VERSION 5.7 ;
  NOWIREEXTENSIONATPIN ON ;
  DIVIDERCHAR "/" ;
  BUSBITCHARS "[]" ;
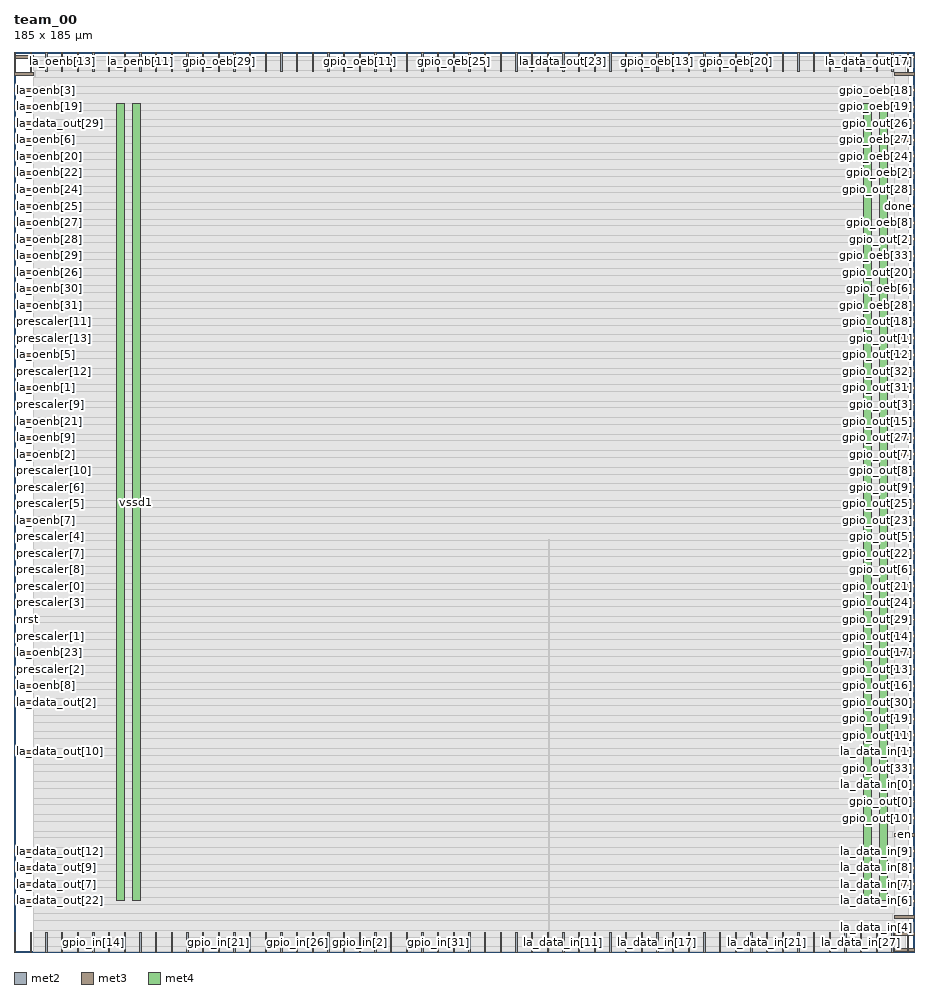
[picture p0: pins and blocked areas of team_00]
MACRO team_00
  CLASS BLOCK ;
  FOREIGN team_00 ;
  ORIGIN 0.000 0.000 ;
  SIZE 185.000 BY 185.000 ;
  PIN clk
    DIRECTION INPUT ;
    USE SIGNAL ;
    ANTENNAGATEAREA 1.286700 ;
    ANTENNADIFFAREA 0.434700 ;
    PORT
      LAYER met2 ;
        RECT 67.710 0.000 67.990 4.000 ;
    END
  END clk
  PIN done
    DIRECTION OUTPUT ;
    USE SIGNAL ;
    ANTENNADIFFAREA 0.445500 ;
    PORT
      LAYER met3 ;
        RECT 181.000 153.040 185.000 153.640 ;
    END
  END done
  PIN en
    DIRECTION INPUT ;
    USE SIGNAL ;
    ANTENNAGATEAREA 0.647700 ;
    ANTENNADIFFAREA 0.434700 ;
    PORT
      LAYER met3 ;
        RECT 181.000 23.840 185.000 24.440 ;
    END
  END en
  PIN gpio_in[0]
    DIRECTION INPUT ;
    USE SIGNAL ;
    PORT
      LAYER met2 ;
        RECT 0.090 0.000 0.370 4.000 ;
    END
  END gpio_in[0]
  PIN gpio_in[10]
    DIRECTION INPUT ;
    USE SIGNAL ;
    PORT
      LAYER met2 ;
        RECT 3.310 0.000 3.590 4.000 ;
    END
  END gpio_in[10]
  PIN gpio_in[11]
    DIRECTION INPUT ;
    USE SIGNAL ;
    PORT
      LAYER met2 ;
        RECT 6.530 0.000 6.810 4.000 ;
    END
  END gpio_in[11]
  PIN gpio_in[12]
    DIRECTION INPUT ;
    USE SIGNAL ;
    PORT
      LAYER met2 ;
        RECT 9.750 0.000 10.030 4.000 ;
    END
  END gpio_in[12]
  PIN gpio_in[13]
    DIRECTION INPUT ;
    USE SIGNAL ;
    PORT
      LAYER met2 ;
        RECT 12.970 0.000 13.250 4.000 ;
    END
  END gpio_in[13]
  PIN gpio_in[14]
    DIRECTION INPUT ;
    USE SIGNAL ;
    PORT
      LAYER met2 ;
        RECT 16.190 0.000 16.470 4.000 ;
    END
  END gpio_in[14]
  PIN gpio_in[15]
    DIRECTION INPUT ;
    USE SIGNAL ;
    PORT
      LAYER met2 ;
        RECT 19.410 0.000 19.690 4.000 ;
    END
  END gpio_in[15]
  PIN gpio_in[16]
    DIRECTION INPUT ;
    USE SIGNAL ;
    PORT
      LAYER met2 ;
        RECT 22.630 0.000 22.910 4.000 ;
    END
  END gpio_in[16]
  PIN gpio_in[17]
    DIRECTION INPUT ;
    USE SIGNAL ;
    PORT
      LAYER met2 ;
        RECT 25.850 0.000 26.130 4.000 ;
    END
  END gpio_in[17]
  PIN gpio_in[18]
    DIRECTION INPUT ;
    USE SIGNAL ;
    PORT
      LAYER met2 ;
        RECT 29.070 0.000 29.350 4.000 ;
    END
  END gpio_in[18]
  PIN gpio_in[19]
    DIRECTION INPUT ;
    USE SIGNAL ;
    PORT
      LAYER met2 ;
        RECT 32.290 0.000 32.570 4.000 ;
    END
  END gpio_in[19]
  PIN gpio_in[1]
    DIRECTION INPUT ;
    USE SIGNAL ;
    PORT
      LAYER met2 ;
        RECT 35.510 0.000 35.790 4.000 ;
    END
  END gpio_in[1]
  PIN gpio_in[20]
    DIRECTION INPUT ;
    USE SIGNAL ;
    PORT
      LAYER met2 ;
        RECT 38.730 0.000 39.010 4.000 ;
    END
  END gpio_in[20]
  PIN gpio_in[21]
    DIRECTION INPUT ;
    USE SIGNAL ;
    PORT
      LAYER met2 ;
        RECT 41.950 0.000 42.230 4.000 ;
    END
  END gpio_in[21]
  PIN gpio_in[22]
    DIRECTION INPUT ;
    USE SIGNAL ;
    PORT
      LAYER met2 ;
        RECT 45.170 0.000 45.450 4.000 ;
    END
  END gpio_in[22]
  PIN gpio_in[23]
    DIRECTION INPUT ;
    USE SIGNAL ;
    PORT
      LAYER met2 ;
        RECT 48.390 0.000 48.670 4.000 ;
    END
  END gpio_in[23]
  PIN gpio_in[24]
    DIRECTION INPUT ;
    USE SIGNAL ;
    PORT
      LAYER met2 ;
        RECT 51.610 0.000 51.890 4.000 ;
    END
  END gpio_in[24]
  PIN gpio_in[25]
    DIRECTION INPUT ;
    USE SIGNAL ;
    PORT
      LAYER met2 ;
        RECT 54.830 0.000 55.110 4.000 ;
    END
  END gpio_in[25]
  PIN gpio_in[26]
    DIRECTION INPUT ;
    USE SIGNAL ;
    PORT
      LAYER met2 ;
        RECT 58.050 0.000 58.330 4.000 ;
    END
  END gpio_in[26]
  PIN gpio_in[27]
    DIRECTION INPUT ;
    USE SIGNAL ;
    PORT
      LAYER met2 ;
        RECT 61.270 0.000 61.550 4.000 ;
    END
  END gpio_in[27]
  PIN gpio_in[28]
    DIRECTION INPUT ;
    USE SIGNAL ;
    PORT
      LAYER met2 ;
        RECT 64.490 0.000 64.770 4.000 ;
    END
  END gpio_in[28]
  PIN gpio_in[29]
    DIRECTION INPUT ;
    USE SIGNAL ;
    PORT
      LAYER met2 ;
        RECT 77.370 0.000 77.650 4.000 ;
    END
  END gpio_in[29]
  PIN gpio_in[2]
    DIRECTION INPUT ;
    USE SIGNAL ;
    PORT
      LAYER met2 ;
        RECT 70.930 0.000 71.210 4.000 ;
    END
  END gpio_in[2]
  PIN gpio_in[30]
    DIRECTION INPUT ;
    USE SIGNAL ;
    PORT
      LAYER met2 ;
        RECT 74.150 0.000 74.430 4.000 ;
    END
  END gpio_in[30]
  PIN gpio_in[31]
    DIRECTION INPUT ;
    USE SIGNAL ;
    PORT
      LAYER met2 ;
        RECT 87.030 0.000 87.310 4.000 ;
    END
  END gpio_in[31]
  PIN gpio_in[32]
    DIRECTION INPUT ;
    USE SIGNAL ;
    PORT
      LAYER met2 ;
        RECT 80.590 0.000 80.870 4.000 ;
    END
  END gpio_in[32]
  PIN gpio_in[33]
    DIRECTION INPUT ;
    USE SIGNAL ;
    PORT
      LAYER met2 ;
        RECT 83.810 0.000 84.090 4.000 ;
    END
  END gpio_in[33]
  PIN gpio_in[3]
    DIRECTION INPUT ;
    USE SIGNAL ;
    PORT
      LAYER met2 ;
        RECT 96.690 0.000 96.970 4.000 ;
    END
  END gpio_in[3]
  PIN gpio_in[4]
    DIRECTION INPUT ;
    USE SIGNAL ;
    PORT
      LAYER met2 ;
        RECT 90.250 0.000 90.530 4.000 ;
    END
  END gpio_in[4]
  PIN gpio_in[5]
    DIRECTION INPUT ;
    USE SIGNAL ;
    PORT
      LAYER met2 ;
        RECT 93.470 0.000 93.750 4.000 ;
    END
  END gpio_in[5]
  PIN gpio_in[6]
    DIRECTION INPUT ;
    USE SIGNAL ;
    PORT
      LAYER met2 ;
        RECT 106.350 0.000 106.630 4.000 ;
    END
  END gpio_in[6]
  PIN gpio_in[7]
    DIRECTION INPUT ;
    USE SIGNAL ;
    PORT
      LAYER met2 ;
        RECT 99.910 0.000 100.190 4.000 ;
    END
  END gpio_in[7]
  PIN gpio_in[8]
    DIRECTION INPUT ;
    USE SIGNAL ;
    PORT
      LAYER met2 ;
        RECT 103.130 0.000 103.410 4.000 ;
    END
  END gpio_in[8]
  PIN gpio_in[9]
    DIRECTION INPUT ;
    USE SIGNAL ;
    PORT
      LAYER met2 ;
        RECT 116.010 0.000 116.290 4.000 ;
    END
  END gpio_in[9]
  PIN gpio_oeb[0]
    DIRECTION OUTPUT ;
    USE SIGNAL ;
    ANTENNADIFFAREA 0.445500 ;
    PORT
      LAYER met2 ;
        RECT 29.070 181.000 29.350 185.000 ;
    END
  END gpio_oeb[0]
  PIN gpio_oeb[10]
    DIRECTION OUTPUT ;
    USE SIGNAL ;
    ANTENNADIFFAREA 0.445500 ;
    PORT
      LAYER met2 ;
        RECT 61.270 181.000 61.550 185.000 ;
    END
  END gpio_oeb[10]
  PIN gpio_oeb[11]
    DIRECTION OUTPUT ;
    USE SIGNAL ;
    ANTENNADIFFAREA 0.445500 ;
    PORT
      LAYER met2 ;
        RECT 70.930 181.000 71.210 185.000 ;
    END
  END gpio_oeb[11]
  PIN gpio_oeb[12]
    DIRECTION OUTPUT ;
    USE SIGNAL ;
    ANTENNADIFFAREA 0.445500 ;
    PORT
      LAYER met3 ;
        RECT 181.000 183.640 185.000 184.240 ;
    END
  END gpio_oeb[12]
  PIN gpio_oeb[13]
    DIRECTION OUTPUT ;
    USE SIGNAL ;
    ANTENNADIFFAREA 0.445500 ;
    PORT
      LAYER met2 ;
        RECT 132.110 181.000 132.390 185.000 ;
    END
  END gpio_oeb[13]
  PIN gpio_oeb[14]
    DIRECTION OUTPUT ;
    USE SIGNAL ;
    ANTENNADIFFAREA 0.445500 ;
    PORT
      LAYER met2 ;
        RECT 135.330 181.000 135.610 185.000 ;
    END
  END gpio_oeb[14]
  PIN gpio_oeb[15]
    DIRECTION OUTPUT ;
    USE SIGNAL ;
    ANTENNADIFFAREA 0.445500 ;
    PORT
      LAYER met2 ;
        RECT 51.610 181.000 51.890 185.000 ;
    END
  END gpio_oeb[15]
  PIN gpio_oeb[16]
    DIRECTION OUTPUT ;
    USE SIGNAL ;
    ANTENNADIFFAREA 0.445500 ;
    PORT
      LAYER met2 ;
        RECT 58.050 181.000 58.330 185.000 ;
    END
  END gpio_oeb[16]
  PIN gpio_oeb[17]
    DIRECTION OUTPUT ;
    USE SIGNAL ;
    ANTENNADIFFAREA 0.445500 ;
    PORT
      LAYER met2 ;
        RECT 45.170 181.000 45.450 185.000 ;
    END
  END gpio_oeb[17]
  PIN gpio_oeb[18]
    DIRECTION OUTPUT ;
    USE SIGNAL ;
    ANTENNADIFFAREA 0.445500 ;
    PORT
      LAYER met3 ;
        RECT 181.000 176.840 185.000 177.440 ;
    END
  END gpio_oeb[18]
  PIN gpio_oeb[19]
    DIRECTION OUTPUT ;
    USE SIGNAL ;
    ANTENNADIFFAREA 0.445500 ;
    PORT
      LAYER met3 ;
        RECT 181.000 173.440 185.000 174.040 ;
    END
  END gpio_oeb[19]
  PIN gpio_oeb[1]
    DIRECTION OUTPUT ;
    USE SIGNAL ;
    ANTENNADIFFAREA 0.445500 ;
    PORT
      LAYER met2 ;
        RECT 67.710 181.000 67.990 185.000 ;
    END
  END gpio_oeb[1]
  PIN gpio_oeb[20]
    DIRECTION OUTPUT ;
    USE SIGNAL ;
    ANTENNADIFFAREA 0.445500 ;
    PORT
      LAYER met2 ;
        RECT 148.210 181.000 148.490 185.000 ;
    END
  END gpio_oeb[20]
  PIN gpio_oeb[21]
    DIRECTION OUTPUT ;
    USE SIGNAL ;
    ANTENNADIFFAREA 0.445500 ;
    PORT
      LAYER met2 ;
        RECT 138.550 181.000 138.830 185.000 ;
    END
  END gpio_oeb[21]
  PIN gpio_oeb[22]
    DIRECTION OUTPUT ;
    USE SIGNAL ;
    ANTENNADIFFAREA 0.445500 ;
    PORT
      LAYER met2 ;
        RECT 74.150 181.000 74.430 185.000 ;
    END
  END gpio_oeb[22]
  PIN gpio_oeb[23]
    DIRECTION OUTPUT ;
    USE SIGNAL ;
    ANTENNADIFFAREA 0.445500 ;
    PORT
      LAYER met2 ;
        RECT 106.350 181.000 106.630 185.000 ;
    END
  END gpio_oeb[23]
  PIN gpio_oeb[24]
    DIRECTION OUTPUT ;
    USE SIGNAL ;
    ANTENNADIFFAREA 0.445500 ;
    PORT
      LAYER met3 ;
        RECT 181.000 163.240 185.000 163.840 ;
    END
  END gpio_oeb[24]
  PIN gpio_oeb[25]
    DIRECTION OUTPUT ;
    USE SIGNAL ;
    ANTENNADIFFAREA 0.445500 ;
    PORT
      LAYER met2 ;
        RECT 90.250 181.000 90.530 185.000 ;
    END
  END gpio_oeb[25]
  PIN gpio_oeb[26]
    DIRECTION OUTPUT ;
    USE SIGNAL ;
    ANTENNADIFFAREA 0.445500 ;
    PORT
      LAYER met2 ;
        RECT 80.590 181.000 80.870 185.000 ;
    END
  END gpio_oeb[26]
  PIN gpio_oeb[27]
    DIRECTION OUTPUT ;
    USE SIGNAL ;
    ANTENNADIFFAREA 0.445500 ;
    PORT
      LAYER met3 ;
        RECT 181.000 166.640 185.000 167.240 ;
    END
  END gpio_oeb[27]
  PIN gpio_oeb[28]
    DIRECTION OUTPUT ;
    USE SIGNAL ;
    ANTENNADIFFAREA 0.445500 ;
    PORT
      LAYER met3 ;
        RECT 181.000 132.640 185.000 133.240 ;
    END
  END gpio_oeb[28]
  PIN gpio_oeb[29]
    DIRECTION OUTPUT ;
    USE SIGNAL ;
    ANTENNADIFFAREA 0.445500 ;
    PORT
      LAYER met2 ;
        RECT 41.950 181.000 42.230 185.000 ;
    END
  END gpio_oeb[29]
  PIN gpio_oeb[2]
    DIRECTION OUTPUT ;
    USE SIGNAL ;
    ANTENNADIFFAREA 0.445500 ;
    PORT
      LAYER met3 ;
        RECT 181.000 159.840 185.000 160.440 ;
    END
  END gpio_oeb[2]
  PIN gpio_oeb[30]
    DIRECTION OUTPUT ;
    USE SIGNAL ;
    ANTENNADIFFAREA 0.445500 ;
    PORT
      LAYER met2 ;
        RECT 83.810 181.000 84.090 185.000 ;
    END
  END gpio_oeb[30]
  PIN gpio_oeb[31]
    DIRECTION OUTPUT ;
    USE SIGNAL ;
    ANTENNADIFFAREA 0.445500 ;
    PORT
      LAYER met2 ;
        RECT 32.290 181.000 32.570 185.000 ;
    END
  END gpio_oeb[31]
  PIN gpio_oeb[32]
    DIRECTION OUTPUT ;
    USE SIGNAL ;
    ANTENNADIFFAREA 0.445500 ;
    PORT
      LAYER met2 ;
        RECT 77.370 181.000 77.650 185.000 ;
    END
  END gpio_oeb[32]
  PIN gpio_oeb[33]
    DIRECTION OUTPUT ;
    USE SIGNAL ;
    ANTENNADIFFAREA 0.445500 ;
    PORT
      LAYER met3 ;
        RECT 181.000 142.840 185.000 143.440 ;
    END
  END gpio_oeb[33]
  PIN gpio_oeb[3]
    DIRECTION OUTPUT ;
    USE SIGNAL ;
    ANTENNADIFFAREA 0.445500 ;
    PORT
      LAYER met2 ;
        RECT 122.450 181.000 122.730 185.000 ;
    END
  END gpio_oeb[3]
  PIN gpio_oeb[4]
    DIRECTION OUTPUT ;
    USE SIGNAL ;
    ANTENNADIFFAREA 0.445500 ;
    PORT
      LAYER met2 ;
        RECT 99.910 181.000 100.190 185.000 ;
    END
  END gpio_oeb[4]
  PIN gpio_oeb[5]
    DIRECTION OUTPUT ;
    USE SIGNAL ;
    ANTENNADIFFAREA 0.445500 ;
    PORT
      LAYER met2 ;
        RECT 48.390 181.000 48.670 185.000 ;
    END
  END gpio_oeb[5]
  PIN gpio_oeb[6]
    DIRECTION OUTPUT ;
    USE SIGNAL ;
    ANTENNADIFFAREA 0.445500 ;
    PORT
      LAYER met3 ;
        RECT 181.000 136.040 185.000 136.640 ;
    END
  END gpio_oeb[6]
  PIN gpio_oeb[7]
    DIRECTION OUTPUT ;
    USE SIGNAL ;
    ANTENNADIFFAREA 0.445500 ;
    PORT
      LAYER met2 ;
        RECT 38.730 181.000 39.010 185.000 ;
    END
  END gpio_oeb[7]
  PIN gpio_oeb[8]
    DIRECTION OUTPUT ;
    USE SIGNAL ;
    ANTENNADIFFAREA 0.445500 ;
    PORT
      LAYER met3 ;
        RECT 181.000 149.640 185.000 150.240 ;
    END
  END gpio_oeb[8]
  PIN gpio_oeb[9]
    DIRECTION OUTPUT ;
    USE SIGNAL ;
    ANTENNADIFFAREA 0.445500 ;
    PORT
      LAYER met2 ;
        RECT 87.030 181.000 87.310 185.000 ;
    END
  END gpio_oeb[9]
  PIN gpio_out[0]
    DIRECTION OUTPUT ;
    USE SIGNAL ;
    ANTENNADIFFAREA 0.445500 ;
    PORT
      LAYER met3 ;
        RECT 181.000 30.640 185.000 31.240 ;
    END
  END gpio_out[0]
  PIN gpio_out[10]
    DIRECTION OUTPUT ;
    USE SIGNAL ;
    ANTENNADIFFAREA 0.445500 ;
    PORT
      LAYER met3 ;
        RECT 181.000 27.240 185.000 27.840 ;
    END
  END gpio_out[10]
  PIN gpio_out[11]
    DIRECTION OUTPUT ;
    USE SIGNAL ;
    ANTENNADIFFAREA 0.445500 ;
    PORT
      LAYER met3 ;
        RECT 181.000 44.240 185.000 44.840 ;
    END
  END gpio_out[11]
  PIN gpio_out[12]
    DIRECTION OUTPUT ;
    USE SIGNAL ;
    ANTENNADIFFAREA 0.445500 ;
    PORT
      LAYER met3 ;
        RECT 181.000 122.440 185.000 123.040 ;
    END
  END gpio_out[12]
  PIN gpio_out[13]
    DIRECTION OUTPUT ;
    USE SIGNAL ;
    ANTENNADIFFAREA 0.445500 ;
    PORT
      LAYER met3 ;
        RECT 181.000 57.840 185.000 58.440 ;
    END
  END gpio_out[13]
  PIN gpio_out[14]
    DIRECTION OUTPUT ;
    USE SIGNAL ;
    ANTENNADIFFAREA 0.445500 ;
    PORT
      LAYER met3 ;
        RECT 181.000 64.640 185.000 65.240 ;
    END
  END gpio_out[14]
  PIN gpio_out[15]
    DIRECTION OUTPUT ;
    USE SIGNAL ;
    ANTENNADIFFAREA 0.445500 ;
    PORT
      LAYER met3 ;
        RECT 181.000 108.840 185.000 109.440 ;
    END
  END gpio_out[15]
  PIN gpio_out[16]
    DIRECTION OUTPUT ;
    USE SIGNAL ;
    ANTENNADIFFAREA 0.445500 ;
    PORT
      LAYER met3 ;
        RECT 181.000 54.440 185.000 55.040 ;
    END
  END gpio_out[16]
  PIN gpio_out[17]
    DIRECTION OUTPUT ;
    USE SIGNAL ;
    ANTENNADIFFAREA 0.445500 ;
    PORT
      LAYER met3 ;
        RECT 181.000 61.240 185.000 61.840 ;
    END
  END gpio_out[17]
  PIN gpio_out[18]
    DIRECTION OUTPUT ;
    USE SIGNAL ;
    ANTENNADIFFAREA 0.445500 ;
    PORT
      LAYER met3 ;
        RECT 181.000 129.240 185.000 129.840 ;
    END
  END gpio_out[18]
  PIN gpio_out[19]
    DIRECTION OUTPUT ;
    USE SIGNAL ;
    ANTENNADIFFAREA 0.445500 ;
    PORT
      LAYER met3 ;
        RECT 181.000 47.640 185.000 48.240 ;
    END
  END gpio_out[19]
  PIN gpio_out[1]
    DIRECTION OUTPUT ;
    USE SIGNAL ;
    ANTENNADIFFAREA 0.445500 ;
    PORT
      LAYER met3 ;
        RECT 181.000 125.840 185.000 126.440 ;
    END
  END gpio_out[1]
  PIN gpio_out[20]
    DIRECTION OUTPUT ;
    USE SIGNAL ;
    ANTENNADIFFAREA 0.445500 ;
    PORT
      LAYER met3 ;
        RECT 181.000 139.440 185.000 140.040 ;
    END
  END gpio_out[20]
  PIN gpio_out[21]
    DIRECTION OUTPUT ;
    USE SIGNAL ;
    ANTENNADIFFAREA 0.445500 ;
    PORT
      LAYER met3 ;
        RECT 181.000 74.840 185.000 75.440 ;
    END
  END gpio_out[21]
  PIN gpio_out[22]
    DIRECTION OUTPUT ;
    USE SIGNAL ;
    ANTENNADIFFAREA 0.445500 ;
    PORT
      LAYER met3 ;
        RECT 181.000 81.640 185.000 82.240 ;
    END
  END gpio_out[22]
  PIN gpio_out[23]
    DIRECTION OUTPUT ;
    USE SIGNAL ;
    ANTENNADIFFAREA 0.445500 ;
    PORT
      LAYER met3 ;
        RECT 181.000 88.440 185.000 89.040 ;
    END
  END gpio_out[23]
  PIN gpio_out[24]
    DIRECTION OUTPUT ;
    USE SIGNAL ;
    ANTENNADIFFAREA 0.445500 ;
    PORT
      LAYER met3 ;
        RECT 181.000 71.440 185.000 72.040 ;
    END
  END gpio_out[24]
  PIN gpio_out[25]
    DIRECTION OUTPUT ;
    USE SIGNAL ;
    ANTENNADIFFAREA 0.445500 ;
    PORT
      LAYER met3 ;
        RECT 181.000 91.840 185.000 92.440 ;
    END
  END gpio_out[25]
  PIN gpio_out[26]
    DIRECTION OUTPUT ;
    USE SIGNAL ;
    ANTENNADIFFAREA 0.445500 ;
    PORT
      LAYER met3 ;
        RECT 181.000 170.040 185.000 170.640 ;
    END
  END gpio_out[26]
  PIN gpio_out[27]
    DIRECTION OUTPUT ;
    USE SIGNAL ;
    ANTENNADIFFAREA 0.445500 ;
    PORT
      LAYER met3 ;
        RECT 181.000 105.440 185.000 106.040 ;
    END
  END gpio_out[27]
  PIN gpio_out[28]
    DIRECTION OUTPUT ;
    USE SIGNAL ;
    ANTENNADIFFAREA 0.445500 ;
    PORT
      LAYER met3 ;
        RECT 181.000 156.440 185.000 157.040 ;
    END
  END gpio_out[28]
  PIN gpio_out[29]
    DIRECTION OUTPUT ;
    USE SIGNAL ;
    ANTENNADIFFAREA 0.445500 ;
    PORT
      LAYER met3 ;
        RECT 181.000 68.040 185.000 68.640 ;
    END
  END gpio_out[29]
  PIN gpio_out[2]
    DIRECTION OUTPUT ;
    USE SIGNAL ;
    ANTENNADIFFAREA 0.445500 ;
    PORT
      LAYER met3 ;
        RECT 181.000 146.240 185.000 146.840 ;
    END
  END gpio_out[2]
  PIN gpio_out[30]
    DIRECTION OUTPUT ;
    USE SIGNAL ;
    ANTENNADIFFAREA 0.445500 ;
    PORT
      LAYER met3 ;
        RECT 181.000 51.040 185.000 51.640 ;
    END
  END gpio_out[30]
  PIN gpio_out[31]
    DIRECTION OUTPUT ;
    USE SIGNAL ;
    ANTENNADIFFAREA 0.445500 ;
    PORT
      LAYER met3 ;
        RECT 181.000 115.640 185.000 116.240 ;
    END
  END gpio_out[31]
  PIN gpio_out[32]
    DIRECTION OUTPUT ;
    USE SIGNAL ;
    ANTENNADIFFAREA 0.445500 ;
    PORT
      LAYER met3 ;
        RECT 181.000 119.040 185.000 119.640 ;
    END
  END gpio_out[32]
  PIN gpio_out[33]
    DIRECTION OUTPUT ;
    USE SIGNAL ;
    ANTENNADIFFAREA 0.445500 ;
    PORT
      LAYER met3 ;
        RECT 181.000 37.440 185.000 38.040 ;
    END
  END gpio_out[33]
  PIN gpio_out[3]
    DIRECTION OUTPUT ;
    USE SIGNAL ;
    ANTENNADIFFAREA 0.445500 ;
    PORT
      LAYER met3 ;
        RECT 181.000 112.240 185.000 112.840 ;
    END
  END gpio_out[3]
  PIN gpio_out[4]
    DIRECTION OUTPUT ;
    USE SIGNAL ;
    ANTENNADIFFAREA 0.445500 ;
    PORT
      LAYER met3 ;
        RECT 181.000 180.240 185.000 180.840 ;
    END
  END gpio_out[4]
  PIN gpio_out[5]
    DIRECTION OUTPUT ;
    USE SIGNAL ;
    ANTENNADIFFAREA 0.445500 ;
    PORT
      LAYER met3 ;
        RECT 181.000 85.040 185.000 85.640 ;
    END
  END gpio_out[5]
  PIN gpio_out[6]
    DIRECTION OUTPUT ;
    USE SIGNAL ;
    ANTENNADIFFAREA 0.445500 ;
    PORT
      LAYER met3 ;
        RECT 181.000 78.240 185.000 78.840 ;
    END
  END gpio_out[6]
  PIN gpio_out[7]
    DIRECTION OUTPUT ;
    USE SIGNAL ;
    ANTENNADIFFAREA 0.445500 ;
    PORT
      LAYER met3 ;
        RECT 181.000 102.040 185.000 102.640 ;
    END
  END gpio_out[7]
  PIN gpio_out[8]
    DIRECTION OUTPUT ;
    USE SIGNAL ;
    ANTENNADIFFAREA 0.445500 ;
    PORT
      LAYER met3 ;
        RECT 181.000 98.640 185.000 99.240 ;
    END
  END gpio_out[8]
  PIN gpio_out[9]
    DIRECTION OUTPUT ;
    USE SIGNAL ;
    ANTENNADIFFAREA 0.445500 ;
    PORT
      LAYER met3 ;
        RECT 181.000 95.240 185.000 95.840 ;
    END
  END gpio_out[9]
  PIN la_data_in[0]
    DIRECTION INPUT ;
    USE SIGNAL ;
    ANTENNAGATEAREA 0.631200 ;
    ANTENNADIFFAREA 0.434700 ;
    PORT
      LAYER met3 ;
        RECT 181.000 34.040 185.000 34.640 ;
    END
  END la_data_in[0]
  PIN la_data_in[10]
    DIRECTION INPUT ;
    USE SIGNAL ;
    PORT
      LAYER met2 ;
        RECT 109.570 0.000 109.850 4.000 ;
    END
  END la_data_in[10]
  PIN la_data_in[11]
    DIRECTION INPUT ;
    USE SIGNAL ;
    PORT
      LAYER met2 ;
        RECT 112.790 0.000 113.070 4.000 ;
    END
  END la_data_in[11]
  PIN la_data_in[12]
    DIRECTION INPUT ;
    USE SIGNAL ;
    PORT
      LAYER met2 ;
        RECT 125.670 0.000 125.950 4.000 ;
    END
  END la_data_in[12]
  PIN la_data_in[13]
    DIRECTION INPUT ;
    USE SIGNAL ;
    PORT
      LAYER met2 ;
        RECT 119.230 0.000 119.510 4.000 ;
    END
  END la_data_in[13]
  PIN la_data_in[14]
    DIRECTION INPUT ;
    USE SIGNAL ;
    PORT
      LAYER met2 ;
        RECT 122.450 0.000 122.730 4.000 ;
    END
  END la_data_in[14]
  PIN la_data_in[15]
    DIRECTION INPUT ;
    USE SIGNAL ;
    PORT
      LAYER met2 ;
        RECT 135.330 0.000 135.610 4.000 ;
    END
  END la_data_in[15]
  PIN la_data_in[16]
    DIRECTION INPUT ;
    USE SIGNAL ;
    PORT
      LAYER met2 ;
        RECT 128.890 0.000 129.170 4.000 ;
    END
  END la_data_in[16]
  PIN la_data_in[17]
    DIRECTION INPUT ;
    USE SIGNAL ;
    PORT
      LAYER met2 ;
        RECT 132.110 0.000 132.390 4.000 ;
    END
  END la_data_in[17]
  PIN la_data_in[18]
    DIRECTION INPUT ;
    USE SIGNAL ;
    PORT
      LAYER met2 ;
        RECT 144.990 0.000 145.270 4.000 ;
    END
  END la_data_in[18]
  PIN la_data_in[19]
    DIRECTION INPUT ;
    USE SIGNAL ;
    PORT
      LAYER met2 ;
        RECT 138.550 0.000 138.830 4.000 ;
    END
  END la_data_in[19]
  PIN la_data_in[1]
    DIRECTION INPUT ;
    USE SIGNAL ;
    ANTENNAGATEAREA 0.631200 ;
    ANTENNADIFFAREA 0.434700 ;
    PORT
      LAYER met3 ;
        RECT 181.000 40.840 185.000 41.440 ;
    END
  END la_data_in[1]
  PIN la_data_in[20]
    DIRECTION INPUT ;
    USE SIGNAL ;
    PORT
      LAYER met2 ;
        RECT 141.770 0.000 142.050 4.000 ;
    END
  END la_data_in[20]
  PIN la_data_in[21]
    DIRECTION INPUT ;
    USE SIGNAL ;
    PORT
      LAYER met2 ;
        RECT 154.650 0.000 154.930 4.000 ;
    END
  END la_data_in[21]
  PIN la_data_in[22]
    DIRECTION INPUT ;
    USE SIGNAL ;
    PORT
      LAYER met2 ;
        RECT 148.210 0.000 148.490 4.000 ;
    END
  END la_data_in[22]
  PIN la_data_in[23]
    DIRECTION INPUT ;
    USE SIGNAL ;
    PORT
      LAYER met2 ;
        RECT 151.430 0.000 151.710 4.000 ;
    END
  END la_data_in[23]
  PIN la_data_in[24]
    DIRECTION INPUT ;
    USE SIGNAL ;
    PORT
      LAYER met2 ;
        RECT 164.310 0.000 164.590 4.000 ;
    END
  END la_data_in[24]
  PIN la_data_in[25]
    DIRECTION INPUT ;
    USE SIGNAL ;
    PORT
      LAYER met2 ;
        RECT 157.870 0.000 158.150 4.000 ;
    END
  END la_data_in[25]
  PIN la_data_in[26]
    DIRECTION INPUT ;
    USE SIGNAL ;
    PORT
      LAYER met2 ;
        RECT 161.090 0.000 161.370 4.000 ;
    END
  END la_data_in[26]
  PIN la_data_in[27]
    DIRECTION INPUT ;
    USE SIGNAL ;
    PORT
      LAYER met2 ;
        RECT 173.970 0.000 174.250 4.000 ;
    END
  END la_data_in[27]
  PIN la_data_in[28]
    DIRECTION INPUT ;
    USE SIGNAL ;
    PORT
      LAYER met2 ;
        RECT 167.530 0.000 167.810 4.000 ;
    END
  END la_data_in[28]
  PIN la_data_in[29]
    DIRECTION INPUT ;
    USE SIGNAL ;
    PORT
      LAYER met2 ;
        RECT 170.750 0.000 171.030 4.000 ;
    END
  END la_data_in[29]
  PIN la_data_in[2]
    DIRECTION INPUT ;
    USE SIGNAL ;
    PORT
      LAYER met2 ;
        RECT 183.630 0.000 183.910 4.000 ;
    END
  END la_data_in[2]
  PIN la_data_in[30]
    DIRECTION INPUT ;
    USE SIGNAL ;
    PORT
      LAYER met2 ;
        RECT 177.190 0.000 177.470 4.000 ;
    END
  END la_data_in[30]
  PIN la_data_in[31]
    DIRECTION INPUT ;
    USE SIGNAL ;
    PORT
      LAYER met2 ;
        RECT 180.410 0.000 180.690 4.000 ;
    END
  END la_data_in[31]
  PIN la_data_in[3]
    DIRECTION INPUT ;
    USE SIGNAL ;
    PORT
      LAYER met3 ;
        RECT 181.000 0.040 185.000 0.640 ;
    END
  END la_data_in[3]
  PIN la_data_in[4]
    DIRECTION INPUT ;
    USE SIGNAL ;
    PORT
      LAYER met3 ;
        RECT 181.000 3.440 185.000 4.040 ;
    END
  END la_data_in[4]
  PIN la_data_in[5]
    DIRECTION INPUT ;
    USE SIGNAL ;
    PORT
      LAYER met3 ;
        RECT 181.000 6.840 185.000 7.440 ;
    END
  END la_data_in[5]
  PIN la_data_in[6]
    DIRECTION INPUT ;
    USE SIGNAL ;
    PORT
      LAYER met3 ;
        RECT 181.000 10.240 185.000 10.840 ;
    END
  END la_data_in[6]
  PIN la_data_in[7]
    DIRECTION INPUT ;
    USE SIGNAL ;
    PORT
      LAYER met3 ;
        RECT 181.000 13.640 185.000 14.240 ;
    END
  END la_data_in[7]
  PIN la_data_in[8]
    DIRECTION INPUT ;
    USE SIGNAL ;
    PORT
      LAYER met3 ;
        RECT 181.000 17.040 185.000 17.640 ;
    END
  END la_data_in[8]
  PIN la_data_in[9]
    DIRECTION INPUT ;
    USE SIGNAL ;
    PORT
      LAYER met3 ;
        RECT 181.000 20.440 185.000 21.040 ;
    END
  END la_data_in[9]
  PIN la_data_out[0]
    DIRECTION OUTPUT ;
    USE SIGNAL ;
    PORT
      LAYER met2 ;
        RECT 22.630 181.000 22.910 185.000 ;
    END
  END la_data_out[0]
  PIN la_data_out[10]
    DIRECTION OUTPUT ;
    USE SIGNAL ;
    PORT
      LAYER met3 ;
        RECT 0.000 40.840 4.000 41.440 ;
    END
  END la_data_out[10]
  PIN la_data_out[11]
    DIRECTION OUTPUT ;
    USE SIGNAL ;
    PORT
      LAYER met2 ;
        RECT 64.490 181.000 64.770 185.000 ;
    END
  END la_data_out[11]
  PIN la_data_out[12]
    DIRECTION OUTPUT ;
    USE SIGNAL ;
    PORT
      LAYER met3 ;
        RECT 0.000 20.440 4.000 21.040 ;
    END
  END la_data_out[12]
  PIN la_data_out[13]
    DIRECTION OUTPUT ;
    USE SIGNAL ;
    PORT
      LAYER met2 ;
        RECT 128.890 181.000 129.170 185.000 ;
    END
  END la_data_out[13]
  PIN la_data_out[14]
    DIRECTION OUTPUT ;
    USE SIGNAL ;
    PORT
      LAYER met2 ;
        RECT 96.690 181.000 96.970 185.000 ;
    END
  END la_data_out[14]
  PIN la_data_out[15]
    DIRECTION OUTPUT ;
    USE SIGNAL ;
    PORT
      LAYER met2 ;
        RECT 154.650 181.000 154.930 185.000 ;
    END
  END la_data_out[15]
  PIN la_data_out[16]
    DIRECTION OUTPUT ;
    USE SIGNAL ;
    PORT
      LAYER met2 ;
        RECT 54.830 181.000 55.110 185.000 ;
    END
  END la_data_out[16]
  PIN la_data_out[17]
    DIRECTION OUTPUT ;
    USE SIGNAL ;
    PORT
      LAYER met2 ;
        RECT 180.410 181.000 180.690 185.000 ;
    END
  END la_data_out[17]
  PIN la_data_out[18]
    DIRECTION OUTPUT ;
    USE SIGNAL ;
    PORT
      LAYER met2 ;
        RECT 177.190 181.000 177.470 185.000 ;
    END
  END la_data_out[18]
  PIN la_data_out[19]
    DIRECTION OUTPUT ;
    USE SIGNAL ;
    PORT
      LAYER met2 ;
        RECT 144.990 181.000 145.270 185.000 ;
    END
  END la_data_out[19]
  PIN la_data_out[1]
    DIRECTION OUTPUT ;
    USE SIGNAL ;
    PORT
      LAYER met2 ;
        RECT 109.570 181.000 109.850 185.000 ;
    END
  END la_data_out[1]
  PIN la_data_out[20]
    DIRECTION OUTPUT ;
    USE SIGNAL ;
    PORT
      LAYER met2 ;
        RECT 170.750 181.000 171.030 185.000 ;
    END
  END la_data_out[20]
  PIN la_data_out[21]
    DIRECTION OUTPUT ;
    USE SIGNAL ;
    PORT
      LAYER met2 ;
        RECT 183.630 181.000 183.910 185.000 ;
    END
  END la_data_out[21]
  PIN la_data_out[22]
    DIRECTION OUTPUT ;
    USE SIGNAL ;
    PORT
      LAYER met3 ;
        RECT 0.000 10.240 4.000 10.840 ;
    END
  END la_data_out[22]
  PIN la_data_out[23]
    DIRECTION OUTPUT ;
    USE SIGNAL ;
    PORT
      LAYER met2 ;
        RECT 112.790 181.000 113.070 185.000 ;
    END
  END la_data_out[23]
  PIN la_data_out[24]
    DIRECTION OUTPUT ;
    USE SIGNAL ;
    PORT
      LAYER met2 ;
        RECT 119.230 181.000 119.510 185.000 ;
    END
  END la_data_out[24]
  PIN la_data_out[25]
    DIRECTION OUTPUT ;
    USE SIGNAL ;
    PORT
      LAYER met2 ;
        RECT 141.770 181.000 142.050 185.000 ;
    END
  END la_data_out[25]
  PIN la_data_out[26]
    DIRECTION OUTPUT ;
    USE SIGNAL ;
    PORT
      LAYER met2 ;
        RECT 157.870 181.000 158.150 185.000 ;
    END
  END la_data_out[26]
  PIN la_data_out[27]
    DIRECTION OUTPUT ;
    USE SIGNAL ;
    PORT
      LAYER met2 ;
        RECT 151.430 181.000 151.710 185.000 ;
    END
  END la_data_out[27]
  PIN la_data_out[28]
    DIRECTION OUTPUT ;
    USE SIGNAL ;
    PORT
      LAYER met2 ;
        RECT 167.530 181.000 167.810 185.000 ;
    END
  END la_data_out[28]
  PIN la_data_out[29]
    DIRECTION OUTPUT ;
    USE SIGNAL ;
    PORT
      LAYER met3 ;
        RECT 0.000 170.040 4.000 170.640 ;
    END
  END la_data_out[29]
  PIN la_data_out[2]
    DIRECTION OUTPUT ;
    USE SIGNAL ;
    PORT
      LAYER met3 ;
        RECT 0.000 51.040 4.000 51.640 ;
    END
  END la_data_out[2]
  PIN la_data_out[30]
    DIRECTION OUTPUT ;
    USE SIGNAL ;
    PORT
      LAYER met2 ;
        RECT 164.310 181.000 164.590 185.000 ;
    END
  END la_data_out[30]
  PIN la_data_out[31]
    DIRECTION OUTPUT ;
    USE SIGNAL ;
    PORT
      LAYER met2 ;
        RECT 116.010 181.000 116.290 185.000 ;
    END
  END la_data_out[31]
  PIN la_data_out[3]
    DIRECTION OUTPUT ;
    USE SIGNAL ;
    PORT
      LAYER met2 ;
        RECT 103.130 181.000 103.410 185.000 ;
    END
  END la_data_out[3]
  PIN la_data_out[4]
    DIRECTION OUTPUT ;
    USE SIGNAL ;
    PORT
      LAYER met2 ;
        RECT 161.090 181.000 161.370 185.000 ;
    END
  END la_data_out[4]
  PIN la_data_out[5]
    DIRECTION OUTPUT ;
    USE SIGNAL ;
    PORT
      LAYER met2 ;
        RECT 173.970 181.000 174.250 185.000 ;
    END
  END la_data_out[5]
  PIN la_data_out[6]
    DIRECTION OUTPUT ;
    USE SIGNAL ;
    PORT
      LAYER met2 ;
        RECT 35.510 181.000 35.790 185.000 ;
    END
  END la_data_out[6]
  PIN la_data_out[7]
    DIRECTION OUTPUT ;
    USE SIGNAL ;
    PORT
      LAYER met3 ;
        RECT 0.000 13.640 4.000 14.240 ;
    END
  END la_data_out[7]
  PIN la_data_out[8]
    DIRECTION OUTPUT ;
    USE SIGNAL ;
    PORT
      LAYER met2 ;
        RECT 125.670 181.000 125.950 185.000 ;
    END
  END la_data_out[8]
  PIN la_data_out[9]
    DIRECTION OUTPUT ;
    USE SIGNAL ;
    PORT
      LAYER met3 ;
        RECT 0.000 17.040 4.000 17.640 ;
    END
  END la_data_out[9]
  PIN la_oenb[0]
    DIRECTION INPUT ;
    USE SIGNAL ;
    ANTENNAGATEAREA 0.631200 ;
    ANTENNADIFFAREA 0.434700 ;
    PORT
      LAYER met2 ;
        RECT 93.470 181.000 93.750 185.000 ;
    END
  END la_oenb[0]
  PIN la_oenb[10]
    DIRECTION INPUT ;
    USE SIGNAL ;
    PORT
      LAYER met2 ;
        RECT 0.090 181.000 0.370 185.000 ;
    END
  END la_oenb[10]
  PIN la_oenb[11]
    DIRECTION INPUT ;
    USE SIGNAL ;
    PORT
      LAYER met2 ;
        RECT 25.850 181.000 26.130 185.000 ;
    END
  END la_oenb[11]
  PIN la_oenb[12]
    DIRECTION INPUT ;
    USE SIGNAL ;
    PORT
      LAYER met2 ;
        RECT 3.310 181.000 3.590 185.000 ;
    END
  END la_oenb[12]
  PIN la_oenb[13]
    DIRECTION INPUT ;
    USE SIGNAL ;
    PORT
      LAYER met2 ;
        RECT 9.750 181.000 10.030 185.000 ;
    END
  END la_oenb[13]
  PIN la_oenb[14]
    DIRECTION INPUT ;
    USE SIGNAL ;
    PORT
      LAYER met2 ;
        RECT 19.410 181.000 19.690 185.000 ;
    END
  END la_oenb[14]
  PIN la_oenb[15]
    DIRECTION INPUT ;
    USE SIGNAL ;
    PORT
      LAYER met2 ;
        RECT 6.530 181.000 6.810 185.000 ;
    END
  END la_oenb[15]
  PIN la_oenb[16]
    DIRECTION INPUT ;
    USE SIGNAL ;
    PORT
      LAYER met2 ;
        RECT 12.970 181.000 13.250 185.000 ;
    END
  END la_oenb[16]
  PIN la_oenb[17]
    DIRECTION INPUT ;
    USE SIGNAL ;
    PORT
      LAYER met2 ;
        RECT 16.190 181.000 16.470 185.000 ;
    END
  END la_oenb[17]
  PIN la_oenb[18]
    DIRECTION INPUT ;
    USE SIGNAL ;
    PORT
      LAYER met3 ;
        RECT 0.000 183.640 4.000 184.240 ;
    END
  END la_oenb[18]
  PIN la_oenb[19]
    DIRECTION INPUT ;
    USE SIGNAL ;
    PORT
      LAYER met3 ;
        RECT 0.000 173.440 4.000 174.040 ;
    END
  END la_oenb[19]
  PIN la_oenb[1]
    DIRECTION INPUT ;
    USE SIGNAL ;
    ANTENNAGATEAREA 0.631200 ;
    ANTENNADIFFAREA 0.434700 ;
    PORT
      LAYER met3 ;
        RECT 0.000 115.640 4.000 116.240 ;
    END
  END la_oenb[1]
  PIN la_oenb[20]
    DIRECTION INPUT ;
    USE SIGNAL ;
    PORT
      LAYER met3 ;
        RECT 0.000 163.240 4.000 163.840 ;
    END
  END la_oenb[20]
  PIN la_oenb[21]
    DIRECTION INPUT ;
    USE SIGNAL ;
    PORT
      LAYER met3 ;
        RECT 0.000 108.840 4.000 109.440 ;
    END
  END la_oenb[21]
  PIN la_oenb[22]
    DIRECTION INPUT ;
    USE SIGNAL ;
    PORT
      LAYER met3 ;
        RECT 0.000 159.840 4.000 160.440 ;
    END
  END la_oenb[22]
  PIN la_oenb[23]
    DIRECTION INPUT ;
    USE SIGNAL ;
    PORT
      LAYER met3 ;
        RECT 0.000 61.240 4.000 61.840 ;
    END
  END la_oenb[23]
  PIN la_oenb[24]
    DIRECTION INPUT ;
    USE SIGNAL ;
    PORT
      LAYER met3 ;
        RECT 0.000 156.440 4.000 157.040 ;
    END
  END la_oenb[24]
  PIN la_oenb[25]
    DIRECTION INPUT ;
    USE SIGNAL ;
    PORT
      LAYER met3 ;
        RECT 0.000 153.040 4.000 153.640 ;
    END
  END la_oenb[25]
  PIN la_oenb[26]
    DIRECTION INPUT ;
    USE SIGNAL ;
    PORT
      LAYER met3 ;
        RECT 0.000 139.440 4.000 140.040 ;
    END
  END la_oenb[26]
  PIN la_oenb[27]
    DIRECTION INPUT ;
    USE SIGNAL ;
    PORT
      LAYER met3 ;
        RECT 0.000 149.640 4.000 150.240 ;
    END
  END la_oenb[27]
  PIN la_oenb[28]
    DIRECTION INPUT ;
    USE SIGNAL ;
    PORT
      LAYER met3 ;
        RECT 0.000 146.240 4.000 146.840 ;
    END
  END la_oenb[28]
  PIN la_oenb[29]
    DIRECTION INPUT ;
    USE SIGNAL ;
    PORT
      LAYER met3 ;
        RECT 0.000 142.840 4.000 143.440 ;
    END
  END la_oenb[29]
  PIN la_oenb[2]
    DIRECTION INPUT ;
    USE SIGNAL ;
    PORT
      LAYER met3 ;
        RECT 0.000 102.040 4.000 102.640 ;
    END
  END la_oenb[2]
  PIN la_oenb[30]
    DIRECTION INPUT ;
    USE SIGNAL ;
    PORT
      LAYER met3 ;
        RECT 0.000 136.040 4.000 136.640 ;
    END
  END la_oenb[30]
  PIN la_oenb[31]
    DIRECTION INPUT ;
    USE SIGNAL ;
    PORT
      LAYER met3 ;
        RECT 0.000 132.640 4.000 133.240 ;
    END
  END la_oenb[31]
  PIN la_oenb[3]
    DIRECTION INPUT ;
    USE SIGNAL ;
    PORT
      LAYER met3 ;
        RECT 0.000 176.840 4.000 177.440 ;
    END
  END la_oenb[3]
  PIN la_oenb[4]
    DIRECTION INPUT ;
    USE SIGNAL ;
    PORT
      LAYER met3 ;
        RECT 0.000 180.240 4.000 180.840 ;
    END
  END la_oenb[4]
  PIN la_oenb[5]
    DIRECTION INPUT ;
    USE SIGNAL ;
    PORT
      LAYER met3 ;
        RECT 0.000 122.440 4.000 123.040 ;
    END
  END la_oenb[5]
  PIN la_oenb[6]
    DIRECTION INPUT ;
    USE SIGNAL ;
    PORT
      LAYER met3 ;
        RECT 0.000 166.640 4.000 167.240 ;
    END
  END la_oenb[6]
  PIN la_oenb[7]
    DIRECTION INPUT ;
    USE SIGNAL ;
    PORT
      LAYER met3 ;
        RECT 0.000 88.440 4.000 89.040 ;
    END
  END la_oenb[7]
  PIN la_oenb[8]
    DIRECTION INPUT ;
    USE SIGNAL ;
    PORT
      LAYER met3 ;
        RECT 0.000 54.440 4.000 55.040 ;
    END
  END la_oenb[8]
  PIN la_oenb[9]
    DIRECTION INPUT ;
    USE SIGNAL ;
    PORT
      LAYER met3 ;
        RECT 0.000 105.440 4.000 106.040 ;
    END
  END la_oenb[9]
  PIN nrst
    DIRECTION INPUT ;
    USE SIGNAL ;
    ANTENNAGATEAREA 0.647700 ;
    ANTENNADIFFAREA 0.434700 ;
    PORT
      LAYER met3 ;
        RECT 0.000 68.040 4.000 68.640 ;
    END
  END nrst
  PIN prescaler[0]
    DIRECTION INPUT ;
    USE SIGNAL ;
    ANTENNAGATEAREA 0.631200 ;
    ANTENNADIFFAREA 0.434700 ;
    PORT
      LAYER met3 ;
        RECT 0.000 74.840 4.000 75.440 ;
    END
  END prescaler[0]
  PIN prescaler[10]
    DIRECTION INPUT ;
    USE SIGNAL ;
    ANTENNAGATEAREA 0.647700 ;
    ANTENNADIFFAREA 0.434700 ;
    PORT
      LAYER met3 ;
        RECT 0.000 98.640 4.000 99.240 ;
    END
  END prescaler[10]
  PIN prescaler[11]
    DIRECTION INPUT ;
    USE SIGNAL ;
    ANTENNAGATEAREA 0.593700 ;
    ANTENNADIFFAREA 0.434700 ;
    PORT
      LAYER met3 ;
        RECT 0.000 129.240 4.000 129.840 ;
    END
  END prescaler[11]
  PIN prescaler[12]
    DIRECTION INPUT ;
    USE SIGNAL ;
    ANTENNAGATEAREA 0.647700 ;
    ANTENNADIFFAREA 0.434700 ;
    PORT
      LAYER met3 ;
        RECT 0.000 119.040 4.000 119.640 ;
    END
  END prescaler[12]
  PIN prescaler[13]
    DIRECTION INPUT ;
    USE SIGNAL ;
    ANTENNAGATEAREA 0.647700 ;
    ANTENNADIFFAREA 0.434700 ;
    PORT
      LAYER met3 ;
        RECT 0.000 125.840 4.000 126.440 ;
    END
  END prescaler[13]
  PIN prescaler[1]
    DIRECTION INPUT ;
    USE SIGNAL ;
    ANTENNAGATEAREA 0.682200 ;
    ANTENNADIFFAREA 0.434700 ;
    PORT
      LAYER met3 ;
        RECT 0.000 64.640 4.000 65.240 ;
    END
  END prescaler[1]
  PIN prescaler[2]
    DIRECTION INPUT ;
    USE SIGNAL ;
    ANTENNAGATEAREA 0.593700 ;
    ANTENNADIFFAREA 0.434700 ;
    PORT
      LAYER met3 ;
        RECT 0.000 57.840 4.000 58.440 ;
    END
  END prescaler[2]
  PIN prescaler[3]
    DIRECTION INPUT ;
    USE SIGNAL ;
    ANTENNAGATEAREA 0.682200 ;
    ANTENNADIFFAREA 0.434700 ;
    PORT
      LAYER met3 ;
        RECT 0.000 71.440 4.000 72.040 ;
    END
  END prescaler[3]
  PIN prescaler[4]
    DIRECTION INPUT ;
    USE SIGNAL ;
    ANTENNAGATEAREA 0.682200 ;
    ANTENNADIFFAREA 0.434700 ;
    PORT
      LAYER met3 ;
        RECT 0.000 85.040 4.000 85.640 ;
    END
  END prescaler[4]
  PIN prescaler[5]
    DIRECTION INPUT ;
    USE SIGNAL ;
    ANTENNAGATEAREA 0.647700 ;
    ANTENNADIFFAREA 0.434700 ;
    PORT
      LAYER met3 ;
        RECT 0.000 91.840 4.000 92.440 ;
    END
  END prescaler[5]
  PIN prescaler[6]
    DIRECTION INPUT ;
    USE SIGNAL ;
    ANTENNAGATEAREA 0.682200 ;
    ANTENNADIFFAREA 0.434700 ;
    PORT
      LAYER met3 ;
        RECT 0.000 95.240 4.000 95.840 ;
    END
  END prescaler[6]
  PIN prescaler[7]
    DIRECTION INPUT ;
    USE SIGNAL ;
    ANTENNAGATEAREA 0.647700 ;
    ANTENNADIFFAREA 0.434700 ;
    PORT
      LAYER met3 ;
        RECT 0.000 81.640 4.000 82.240 ;
    END
  END prescaler[7]
  PIN prescaler[8]
    DIRECTION INPUT ;
    USE SIGNAL ;
    ANTENNAGATEAREA 0.647700 ;
    ANTENNADIFFAREA 0.434700 ;
    PORT
      LAYER met3 ;
        RECT 0.000 78.240 4.000 78.840 ;
    END
  END prescaler[8]
  PIN prescaler[9]
    DIRECTION INPUT ;
    USE SIGNAL ;
    ANTENNAGATEAREA 0.631200 ;
    ANTENNADIFFAREA 0.434700 ;
    PORT
      LAYER met3 ;
        RECT 0.000 112.240 4.000 112.840 ;
    END
  END prescaler[9]
  PIN vccd1
    DIRECTION INOUT ;
    USE POWER ;
    PORT
      LAYER met4 ;
        RECT 21.040 10.640 22.640 174.320 ;
    END
    PORT
      LAYER met4 ;
        RECT 174.640 10.640 176.240 174.320 ;
    END
  END vccd1
  PIN vssd1
    DIRECTION INOUT ;
    USE GROUND ;
    PORT
      LAYER met4 ;
        RECT 24.340 10.640 25.940 174.320 ;
    END
    PORT
      LAYER met4 ;
        RECT 177.940 10.640 179.540 174.320 ;
    END
  END vssd1
  OBS
      LAYER nwell ;
        RECT 5.330 10.760 179.590 174.200 ;
      LAYER li1 ;
        RECT 5.520 10.795 179.400 174.165 ;
      LAYER met1 ;
        RECT 4.210 10.640 183.930 174.320 ;
      LAYER met2 ;
        RECT 4.230 180.720 6.250 184.125 ;
        RECT 7.090 180.720 9.470 184.125 ;
        RECT 10.310 180.720 12.690 184.125 ;
        RECT 13.530 180.720 15.910 184.125 ;
        RECT 16.750 180.720 19.130 184.125 ;
        RECT 19.970 180.720 22.350 184.125 ;
        RECT 23.190 180.720 25.570 184.125 ;
        RECT 26.410 180.720 28.790 184.125 ;
        RECT 29.630 180.720 32.010 184.125 ;
        RECT 32.850 180.720 35.230 184.125 ;
        RECT 36.070 180.720 38.450 184.125 ;
        RECT 39.290 180.720 41.670 184.125 ;
        RECT 42.510 180.720 44.890 184.125 ;
        RECT 45.730 180.720 48.110 184.125 ;
        RECT 48.950 180.720 51.330 184.125 ;
        RECT 52.170 180.720 54.550 184.125 ;
        RECT 55.390 180.720 57.770 184.125 ;
        RECT 58.610 180.720 60.990 184.125 ;
        RECT 61.830 180.720 64.210 184.125 ;
        RECT 65.050 180.720 67.430 184.125 ;
        RECT 68.270 180.720 70.650 184.125 ;
        RECT 71.490 180.720 73.870 184.125 ;
        RECT 74.710 180.720 77.090 184.125 ;
        RECT 77.930 180.720 80.310 184.125 ;
        RECT 81.150 180.720 83.530 184.125 ;
        RECT 84.370 180.720 86.750 184.125 ;
        RECT 87.590 180.720 89.970 184.125 ;
        RECT 90.810 180.720 93.190 184.125 ;
        RECT 94.030 180.720 96.410 184.125 ;
        RECT 97.250 180.720 99.630 184.125 ;
        RECT 100.470 180.720 102.850 184.125 ;
        RECT 103.690 180.720 106.070 184.125 ;
        RECT 106.910 180.720 109.290 184.125 ;
        RECT 110.130 180.720 112.510 184.125 ;
        RECT 113.350 180.720 115.730 184.125 ;
        RECT 116.570 180.720 118.950 184.125 ;
        RECT 119.790 180.720 122.170 184.125 ;
        RECT 123.010 180.720 125.390 184.125 ;
        RECT 126.230 180.720 128.610 184.125 ;
        RECT 129.450 180.720 131.830 184.125 ;
        RECT 132.670 180.720 135.050 184.125 ;
        RECT 135.890 180.720 138.270 184.125 ;
        RECT 139.110 180.720 141.490 184.125 ;
        RECT 142.330 180.720 144.710 184.125 ;
        RECT 145.550 180.720 147.930 184.125 ;
        RECT 148.770 180.720 151.150 184.125 ;
        RECT 151.990 180.720 154.370 184.125 ;
        RECT 155.210 180.720 157.590 184.125 ;
        RECT 158.430 180.720 160.810 184.125 ;
        RECT 161.650 180.720 164.030 184.125 ;
        RECT 164.870 180.720 167.250 184.125 ;
        RECT 168.090 180.720 170.470 184.125 ;
        RECT 171.310 180.720 173.690 184.125 ;
        RECT 174.530 180.720 176.910 184.125 ;
        RECT 177.750 180.720 180.130 184.125 ;
        RECT 180.970 180.720 183.350 184.125 ;
        RECT 4.230 4.280 183.900 180.720 ;
        RECT 4.230 0.155 6.250 4.280 ;
        RECT 7.090 0.155 9.470 4.280 ;
        RECT 10.310 0.155 12.690 4.280 ;
        RECT 13.530 0.155 15.910 4.280 ;
        RECT 16.750 0.155 19.130 4.280 ;
        RECT 19.970 0.155 22.350 4.280 ;
        RECT 23.190 0.155 25.570 4.280 ;
        RECT 26.410 0.155 28.790 4.280 ;
        RECT 29.630 0.155 32.010 4.280 ;
        RECT 32.850 0.155 35.230 4.280 ;
        RECT 36.070 0.155 38.450 4.280 ;
        RECT 39.290 0.155 41.670 4.280 ;
        RECT 42.510 0.155 44.890 4.280 ;
        RECT 45.730 0.155 48.110 4.280 ;
        RECT 48.950 0.155 51.330 4.280 ;
        RECT 52.170 0.155 54.550 4.280 ;
        RECT 55.390 0.155 57.770 4.280 ;
        RECT 58.610 0.155 60.990 4.280 ;
        RECT 61.830 0.155 64.210 4.280 ;
        RECT 65.050 0.155 67.430 4.280 ;
        RECT 68.270 0.155 70.650 4.280 ;
        RECT 71.490 0.155 73.870 4.280 ;
        RECT 74.710 0.155 77.090 4.280 ;
        RECT 77.930 0.155 80.310 4.280 ;
        RECT 81.150 0.155 83.530 4.280 ;
        RECT 84.370 0.155 86.750 4.280 ;
        RECT 87.590 0.155 89.970 4.280 ;
        RECT 90.810 0.155 93.190 4.280 ;
        RECT 94.030 0.155 96.410 4.280 ;
        RECT 97.250 0.155 99.630 4.280 ;
        RECT 100.470 0.155 102.850 4.280 ;
        RECT 103.690 0.155 106.070 4.280 ;
        RECT 106.910 0.155 109.290 4.280 ;
        RECT 110.130 0.155 112.510 4.280 ;
        RECT 113.350 0.155 115.730 4.280 ;
        RECT 116.570 0.155 118.950 4.280 ;
        RECT 119.790 0.155 122.170 4.280 ;
        RECT 123.010 0.155 125.390 4.280 ;
        RECT 126.230 0.155 128.610 4.280 ;
        RECT 129.450 0.155 131.830 4.280 ;
        RECT 132.670 0.155 135.050 4.280 ;
        RECT 135.890 0.155 138.270 4.280 ;
        RECT 139.110 0.155 141.490 4.280 ;
        RECT 142.330 0.155 144.710 4.280 ;
        RECT 145.550 0.155 147.930 4.280 ;
        RECT 148.770 0.155 151.150 4.280 ;
        RECT 151.990 0.155 154.370 4.280 ;
        RECT 155.210 0.155 157.590 4.280 ;
        RECT 158.430 0.155 160.810 4.280 ;
        RECT 161.650 0.155 164.030 4.280 ;
        RECT 164.870 0.155 167.250 4.280 ;
        RECT 168.090 0.155 170.470 4.280 ;
        RECT 171.310 0.155 173.690 4.280 ;
        RECT 174.530 0.155 176.910 4.280 ;
        RECT 177.750 0.155 180.130 4.280 ;
        RECT 180.970 0.155 183.350 4.280 ;
      LAYER met3 ;
        RECT 4.400 183.240 180.600 184.105 ;
        RECT 3.990 181.240 181.000 183.240 ;
        RECT 4.400 179.840 180.600 181.240 ;
        RECT 3.990 177.840 181.000 179.840 ;
        RECT 4.400 176.440 180.600 177.840 ;
        RECT 3.990 174.440 181.000 176.440 ;
        RECT 4.400 173.040 180.600 174.440 ;
        RECT 3.990 171.040 181.000 173.040 ;
        RECT 4.400 169.640 180.600 171.040 ;
        RECT 3.990 167.640 181.000 169.640 ;
        RECT 4.400 166.240 180.600 167.640 ;
        RECT 3.990 164.240 181.000 166.240 ;
        RECT 4.400 162.840 180.600 164.240 ;
        RECT 3.990 160.840 181.000 162.840 ;
        RECT 4.400 159.440 180.600 160.840 ;
        RECT 3.990 157.440 181.000 159.440 ;
        RECT 4.400 156.040 180.600 157.440 ;
        RECT 3.990 154.040 181.000 156.040 ;
        RECT 4.400 152.640 180.600 154.040 ;
        RECT 3.990 150.640 181.000 152.640 ;
        RECT 4.400 149.240 180.600 150.640 ;
        RECT 3.990 147.240 181.000 149.240 ;
        RECT 4.400 145.840 180.600 147.240 ;
        RECT 3.990 143.840 181.000 145.840 ;
        RECT 4.400 142.440 180.600 143.840 ;
        RECT 3.990 140.440 181.000 142.440 ;
        RECT 4.400 139.040 180.600 140.440 ;
        RECT 3.990 137.040 181.000 139.040 ;
        RECT 4.400 135.640 180.600 137.040 ;
        RECT 3.990 133.640 181.000 135.640 ;
        RECT 4.400 132.240 180.600 133.640 ;
        RECT 3.990 130.240 181.000 132.240 ;
        RECT 4.400 128.840 180.600 130.240 ;
        RECT 3.990 126.840 181.000 128.840 ;
        RECT 4.400 125.440 180.600 126.840 ;
        RECT 3.990 123.440 181.000 125.440 ;
        RECT 4.400 122.040 180.600 123.440 ;
        RECT 3.990 120.040 181.000 122.040 ;
        RECT 4.400 118.640 180.600 120.040 ;
        RECT 3.990 116.640 181.000 118.640 ;
        RECT 4.400 115.240 180.600 116.640 ;
        RECT 3.990 113.240 181.000 115.240 ;
        RECT 4.400 111.840 180.600 113.240 ;
        RECT 3.990 109.840 181.000 111.840 ;
        RECT 4.400 108.440 180.600 109.840 ;
        RECT 3.990 106.440 181.000 108.440 ;
        RECT 4.400 105.040 180.600 106.440 ;
        RECT 3.990 103.040 181.000 105.040 ;
        RECT 4.400 101.640 180.600 103.040 ;
        RECT 3.990 99.640 181.000 101.640 ;
        RECT 4.400 98.240 180.600 99.640 ;
        RECT 3.990 96.240 181.000 98.240 ;
        RECT 4.400 94.840 180.600 96.240 ;
        RECT 3.990 92.840 181.000 94.840 ;
        RECT 4.400 91.440 180.600 92.840 ;
        RECT 3.990 89.440 181.000 91.440 ;
        RECT 4.400 88.040 180.600 89.440 ;
        RECT 3.990 86.040 181.000 88.040 ;
        RECT 4.400 84.640 180.600 86.040 ;
        RECT 3.990 82.640 181.000 84.640 ;
        RECT 4.400 81.240 180.600 82.640 ;
        RECT 3.990 79.240 181.000 81.240 ;
        RECT 4.400 77.840 180.600 79.240 ;
        RECT 3.990 75.840 181.000 77.840 ;
        RECT 4.400 74.440 180.600 75.840 ;
        RECT 3.990 72.440 181.000 74.440 ;
        RECT 4.400 71.040 180.600 72.440 ;
        RECT 3.990 69.040 181.000 71.040 ;
        RECT 4.400 67.640 180.600 69.040 ;
        RECT 3.990 65.640 181.000 67.640 ;
        RECT 4.400 64.240 180.600 65.640 ;
        RECT 3.990 62.240 181.000 64.240 ;
        RECT 4.400 60.840 180.600 62.240 ;
        RECT 3.990 58.840 181.000 60.840 ;
        RECT 4.400 57.440 180.600 58.840 ;
        RECT 3.990 55.440 181.000 57.440 ;
        RECT 4.400 54.040 180.600 55.440 ;
        RECT 3.990 52.040 181.000 54.040 ;
        RECT 4.400 50.640 180.600 52.040 ;
        RECT 3.990 48.640 181.000 50.640 ;
        RECT 3.990 47.240 180.600 48.640 ;
        RECT 3.990 45.240 181.000 47.240 ;
        RECT 3.990 43.840 180.600 45.240 ;
        RECT 3.990 41.840 181.000 43.840 ;
        RECT 4.400 40.440 180.600 41.840 ;
        RECT 3.990 38.440 181.000 40.440 ;
        RECT 3.990 37.040 180.600 38.440 ;
        RECT 3.990 35.040 181.000 37.040 ;
        RECT 3.990 33.640 180.600 35.040 ;
        RECT 3.990 31.640 181.000 33.640 ;
        RECT 3.990 30.240 180.600 31.640 ;
        RECT 3.990 28.240 181.000 30.240 ;
        RECT 3.990 26.840 180.600 28.240 ;
        RECT 3.990 24.840 181.000 26.840 ;
        RECT 3.990 23.440 180.600 24.840 ;
        RECT 3.990 21.440 181.000 23.440 ;
        RECT 4.400 20.040 180.600 21.440 ;
        RECT 3.990 18.040 181.000 20.040 ;
        RECT 4.400 16.640 180.600 18.040 ;
        RECT 3.990 14.640 181.000 16.640 ;
        RECT 4.400 13.240 180.600 14.640 ;
        RECT 3.990 11.240 181.000 13.240 ;
        RECT 4.400 9.840 180.600 11.240 ;
        RECT 3.990 7.840 181.000 9.840 ;
        RECT 3.990 6.440 180.600 7.840 ;
        RECT 3.990 4.440 181.000 6.440 ;
        RECT 3.990 3.040 180.600 4.440 ;
        RECT 3.990 1.040 181.000 3.040 ;
        RECT 3.990 0.175 180.600 1.040 ;
      LAYER met4 ;
        RECT 109.775 0.175 110.105 84.825 ;
  END
END team_00
END LIBRARY

